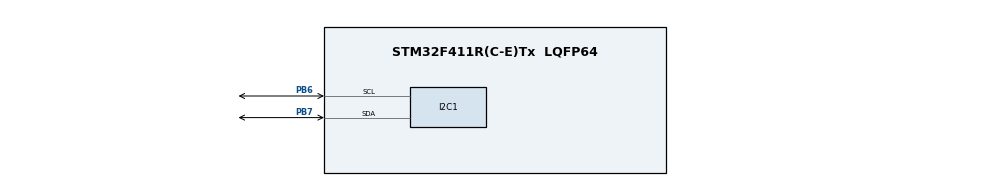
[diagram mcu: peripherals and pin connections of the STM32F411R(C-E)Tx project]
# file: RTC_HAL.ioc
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Mcu.Family=STM32F4
Mcu.Name=STM32F411R(C-E)Tx
Mcu.Package=LQFP64
NVIC.PriorityGroup=NVIC_PRIORITYGROUP_0
NVIC.RTC_Alarm_IRQn=true\:0\:0\:false\:false\:true\:true\:true\:true
PB6.Mode=I2C
PB6.Signal=I2C1_SCL
PB7.Mode=I2C
PB7.Signal=I2C1_SDA
ProjectManager.HeapSize=0x200
ProjectManager.StackSize=0x400
ProjectManager.TargetToolchain=STM32CubeIDE
RCC.48MHZClocksFreq_Value=84000000
RCC.AHBFreq_Value=16000000
RCC.APB1CLKDivider=RCC_HCLK_DIV2
RCC.APB1Freq_Value=8000000
RCC.APB1TimFreq_Value=16000000
RCC.APB2Freq_Value=16000000
RCC.APB2TimFreq_Value=16000000
RCC.CortexFreq_Value=16000000
RCC.FLatency-AdvancedSettings=FLASH_LATENCY_0
RCC.HCLKFreq_Value=16000000
RCC.HSE_VALUE=8000000
RCC.HSI_VALUE=16000000
RCC.LSE_VALUE=32768
RCC.PLLN=336
RCC.PLLP=RCC_PLLP_DIV4
RCC.SYSCLKFreq_VALUE=16000000
RCC.VCOOutputFreq_Value=336000000
RTC.Alarm=RTC_ALARM_A
RTC.Date=31
RTC.Format=RTC_FORMAT_BIN
RTC.Hours=15
RTC.Minutes=59
RTC.Month=RTC_MONTH_DECEMBER
RTC.Seconds=24
RTC.Seconds_A=10
VP_RTC_VS_RTC_Activate.Mode=RTC_Enabled
VP_RTC_VS_RTC_Alarm_A_Intern.Mode=Alarm A
VP_RTC_VS_RTC_Calendar.Mode=RTC_Calendar
board=NUCLEO-F411RE

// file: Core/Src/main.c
/* USER CODE BEGIN Header */
/**
  ******************************************************************************
  * @file           : main.c
  * @brief          : Main program body
  ******************************************************************************
  * @attention
  *
  * Copyright (c) 2022 STMicroelectronics.
  * All rights reserved.
  *
  * This software is licensed under terms that can be found in the LICENSE file
  * in the root directory of this software component.
  * If no LICENSE file comes with this software, it is provided AS-IS.
  *
  ******************************************************************************
  */
/* USER CODE END Header */
#include "main.h"
#include<stdio.h>
#include"lcd.h"

I2C_HandleTypeDef hi2c1;

RTC_HandleTypeDef hrtc;
RTC_TimeTypeDef sTime;
RTC_DateTypeDef sDate;

void SystemClock_Config(void);
static void MX_GPIO_Init(void);
static void MX_I2C1_Init(void);
static void MX_RTC_Init(void);

/* USER CODE BEGIN 0 */
char Time[15];
char Date[15];
/* USER CODE END 0 */

int main(void)
{

  /* MCU Configuration--------------------------------------------------------*/

  /* Reset of all peripherals, Initializes the Flash interface and the Systick. */
  HAL_Init();
  LCD_init();

  /* Configure the system clock */
  SystemClock_Config();

  /* Initialize all configured peripherals */
  MX_GPIO_Init();
  MX_I2C1_Init();
  MX_RTC_Init();
  /* USER CODE BEGIN 2 */
//  SET TIME
 sTime.Hours = 15;
 sTime.Minutes = 59;
 sTime.Seconds = 45;
 HAL_RTC_SetTime(&hrtc, &sTime, RTC_FORMAT_BIN);

//  SET DATE
 sDate.Date = 26;
 sDate.Month = RTC_MONTH_DECEMBER;
 sDate.WeekDay = RTC_WEEKDAY_MONDAY;
 sDate.Year = 22;
 HAL_RTC_SetDate(&hrtc, &sDate, RTC_FORMAT_BIN);
  /* USER CODE END 2 */
 LCD_string("TIME:");
 LCD_command(0xC0);
 LCD_string("DATE:");
  /* Infinite loop */
  while (1)
  {
 HAL_RTC_GetTime(&hrtc, &sTime, RTC_FORMAT_BIN);
 sprintf (Time, "%02d:%02d:%02d", sTime.Hours, sTime.Minutes, sTime.Seconds);

 HAL_RTC_GetDate(&hrtc, &sDate, RTC_FORMAT_BIN);
 sprintf (Date, "%02d-%02d-%02d", sDate.Date, sDate.Month, sDate.Year);

 HAL_Delay(200);

	delay(1);
	LCD_command(0xC6);
	LCD_string(Time);

	delay(1);
	LCD_command(0x86);
	LCD_string(Date);
  }
}

void SystemClock_Config(void)
{
  RCC_OscInitTypeDef RCC_OscInitStruct = {0};
  RCC_ClkInitTypeDef RCC_ClkInitStruct = {0};

  /** Configure the main internal regulator output voltage
  */
  __HAL_RCC_PWR_CLK_ENABLE();
  __HAL_PWR_VOLTAGESCALING_CONFIG(PWR_REGULATOR_VOLTAGE_SCALE1);

  /** Initializes the RCC Oscillators according to the specified parameters
  * in the RCC_OscInitTypeDef structure.
  */
  RCC_OscInitStruct.OscillatorType = RCC_OSCILLATORTYPE_HSI|RCC_OSCILLATORTYPE_LSI;
  RCC_OscInitStruct.HSIState = RCC_HSI_ON;
  RCC_OscInitStruct.HSICalibrationValue = RCC_HSICALIBRATION_DEFAULT;
  RCC_OscInitStruct.LSIState = RCC_LSI_ON;
  RCC_OscInitStruct.PLL.PLLState = RCC_PLL_NONE;
  if (HAL_RCC_OscConfig(&RCC_OscInitStruct) != HAL_OK)
  {
    Error_Handler();
  }

  /** Initializes the CPU, AHB and APB buses clocks
  */
  RCC_ClkInitStruct.ClockType = RCC_CLOCKTYPE_HCLK|RCC_CLOCKTYPE_SYSCLK
                              |RCC_CLOCKTYPE_PCLK1|RCC_CLOCKTYPE_PCLK2;
  RCC_ClkInitStruct.SYSCLKSource = RCC_SYSCLKSOURCE_HSI;
  RCC_ClkInitStruct.AHBCLKDivider = RCC_SYSCLK_DIV1;
  RCC_ClkInitStruct.APB1CLKDivider = RCC_HCLK_DIV1;
  RCC_ClkInitStruct.APB2CLKDivider = RCC_HCLK_DIV1;

  if (HAL_RCC_ClockConfig(&RCC_ClkInitStruct, FLASH_LATENCY_0) != HAL_OK)
  {
    Error_Handler();
  }
}

static void MX_I2C1_Init(void)
{

  hi2c1.Instance = I2C1;
  hi2c1.Init.ClockSpeed = 100000;
  hi2c1.Init.DutyCycle = I2C_DUTYCYCLE_2;
  hi2c1.Init.OwnAddress1 = 0;
  hi2c1.Init.AddressingMode = I2C_ADDRESSINGMODE_7BIT;
  hi2c1.Init.DualAddressMode = I2C_DUALADDRESS_DISABLE;
  hi2c1.Init.OwnAddress2 = 0;
  hi2c1.Init.GeneralCallMode = I2C_GENERALCALL_DISABLE;
  hi2c1.Init.NoStretchMode = I2C_NOSTRETCH_DISABLE;
  if (HAL_I2C_Init(&hi2c1) != HAL_OK)
  {
    Error_Handler();
  }

}

static void MX_RTC_Init(void)
{

  RTC_TimeTypeDef sTime = {0};
  RTC_DateTypeDef sDate = {0};
  RTC_AlarmTypeDef sAlarm = {0};

  /** Initialize RTC Only
  */
  hrtc.Instance = RTC;
  hrtc.Init.HourFormat = RTC_HOURFORMAT_24;
  hrtc.Init.AsynchPrediv = 127;
  hrtc.Init.SynchPrediv = 255;
  hrtc.Init.OutPut = RTC_OUTPUT_DISABLE;
  hrtc.Init.OutPutPolarity = RTC_OUTPUT_POLARITY_HIGH;
  hrtc.Init.OutPutType = RTC_OUTPUT_TYPE_OPENDRAIN;
  if (HAL_RTC_Init(&hrtc) != HAL_OK)
  {
    Error_Handler();
  }

  /** Initialize RTC and set the Time and Date
  */
  sTime.Hours = 15;
  sTime.Minutes = 0;
  sTime.Seconds = 50;
  sTime.DayLightSaving = RTC_DAYLIGHTSAVING_NONE;
  sTime.StoreOperation = RTC_STOREOPERATION_RESET;
  if (HAL_RTC_SetTime(&hrtc, &sTime, RTC_FORMAT_BIN) != HAL_OK)
  {
    Error_Handler();
  }
  sDate.WeekDay = RTC_WEEKDAY_MONDAY;
  sDate.Month = RTC_MONTH_DECEMBER;
  sDate.Date = 31;
  sDate.Year = 22;

  if (HAL_RTC_SetDate(&hrtc, &sDate, RTC_FORMAT_BIN) != HAL_OK)
  {
    Error_Handler();
  }

  /** Enable the Alarm A
  */
  sAlarm.AlarmTime.Hours = 0;
  sAlarm.AlarmTime.Minutes = 0;
  sAlarm.AlarmTime.Seconds = 10;
  sAlarm.AlarmTime.SubSeconds = 0;
  sAlarm.AlarmTime.DayLightSaving = RTC_DAYLIGHTSAVING_NONE;
  sAlarm.AlarmTime.StoreOperation = RTC_STOREOPERATION_RESET;
  sAlarm.AlarmMask = RTC_ALARMMASK_NONE;
  sAlarm.AlarmSubSecondMask = RTC_ALARMSUBSECONDMASK_ALL;
  sAlarm.AlarmDateWeekDaySel = RTC_ALARMDATEWEEKDAYSEL_DATE;
  sAlarm.AlarmDateWeekDay = 1;
  sAlarm.Alarm = RTC_ALARM_A;
  if (HAL_RTC_SetAlarm_IT(&hrtc, &sAlarm, RTC_FORMAT_BIN) != HAL_OK)
  {
    Error_Handler();
  }

}

static void MX_GPIO_Init(void)
{

  /* GPIO Ports Clock Enable */
  __HAL_RCC_GPIOB_CLK_ENABLE();

}

void Error_Handler(void)
{
  __disable_irq();
  while (1)
  {
  }
}
